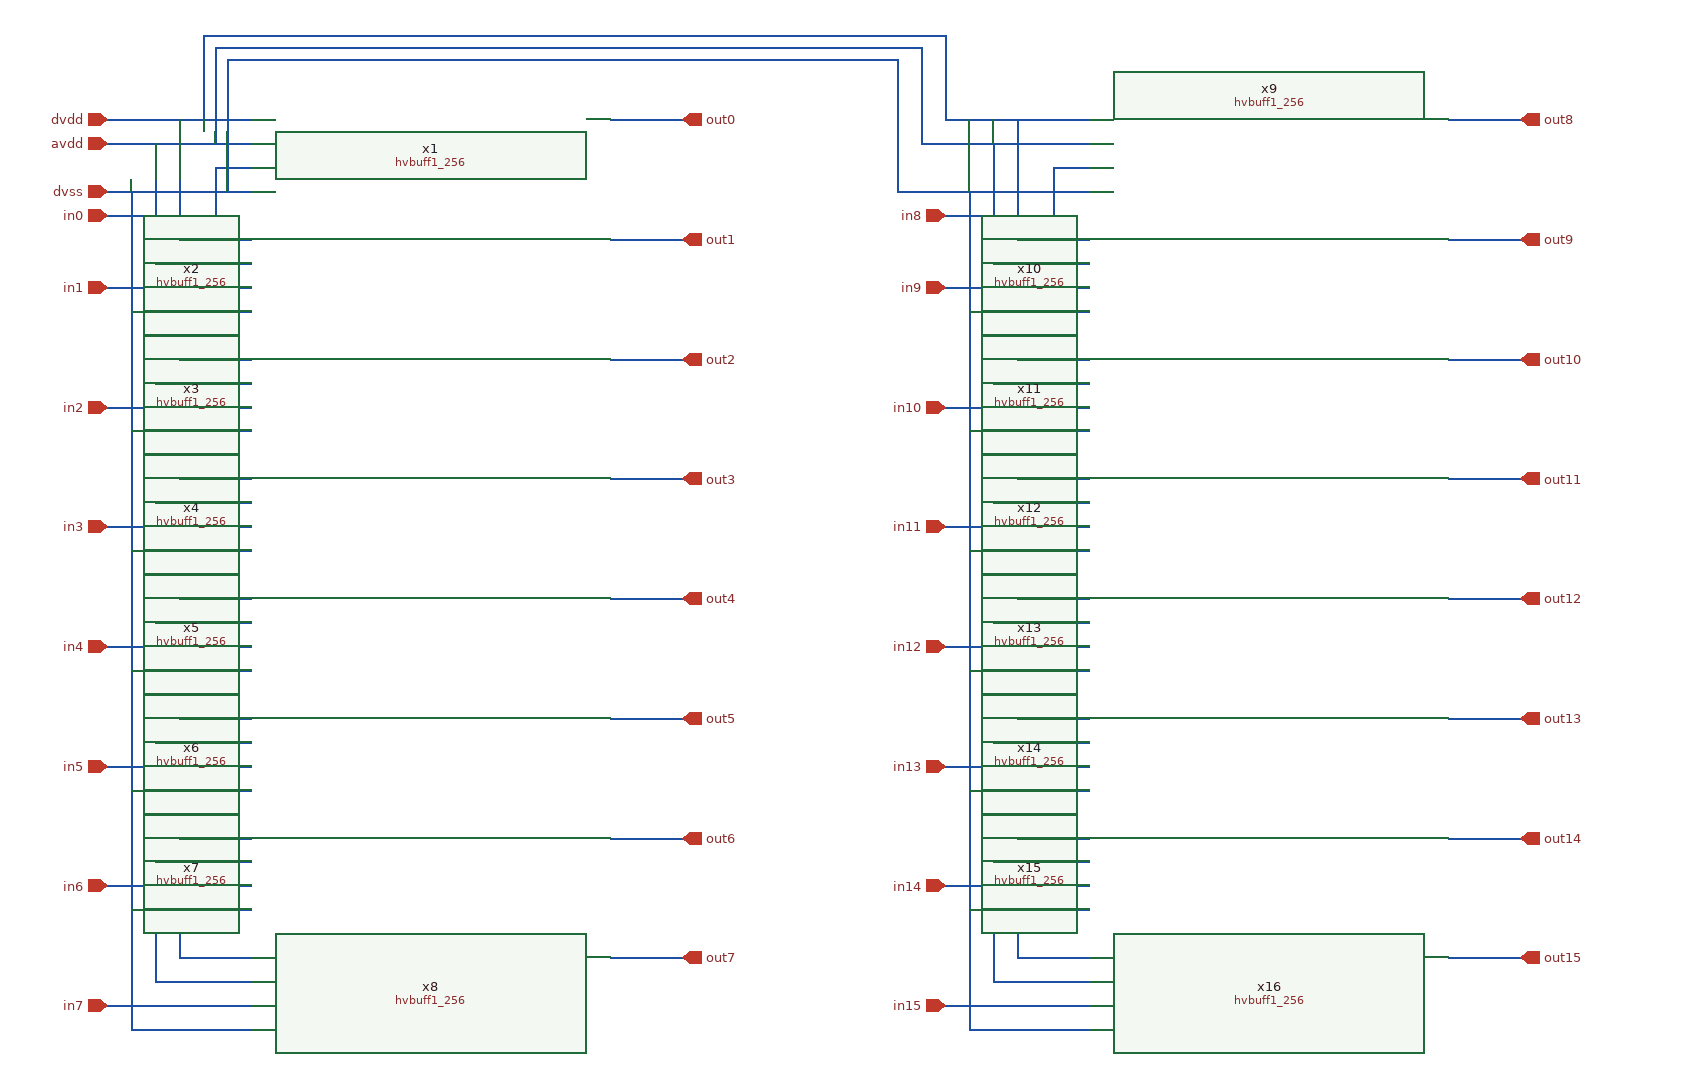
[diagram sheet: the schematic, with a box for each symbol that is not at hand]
v {xschem version=3.4.5 file_version=1.2
}
G {}
K {}
V {}
S {}
E {}
N -250 -70 -130 -70 {
lab=dvdd}
N -190 -70 -190 630 {
lab=dvdd}
N -190 630 -130 630 {
lab=dvdd}
N -190 530 -130 530 {
lab=dvdd}
N -190 430 -130 430 {
lab=dvdd}
N -190 330 -130 330 {
lab=dvdd}
N -190 230 -130 230 {
lab=dvdd}
N -190 130 -130 130 {
lab=dvdd}
N -190 30 -130 30 {
lab=dvdd}
N -250 -50 -130 -50 {
lab=avdd}
N -210 -50 -210 650 {
lab=avdd}
N -210 650 -130 650 {
lab=avdd}
N -210 550 -130 550 {
lab=avdd}
N -210 450 -130 450 {
lab=avdd}
N -210 350 -130 350 {
lab=avdd}
N -210 250 -130 250 {
lab=avdd}
N -210 150 -130 150 {
lab=avdd}
N -210 50 -130 50 {
lab=avdd}
N -250 -10 -130 -10 {
lab=dvss}
N -230 -10 -230 690 {
lab=dvss}
N -230 690 -130 690 {
lab=dvss}
N -230 590 -130 590 {
lab=dvss}
N -230 490 -130 490 {
lab=dvss}
N -230 390 -130 390 {
lab=dvss}
N -230 290 -130 290 {
lab=dvss}
N -230 190 -130 190 {
lab=dvss}
N -230 90 -130 90 {
lab=dvss}
N -160 -30 -130 -30 {
lab=in0}
N -160 -30 -160 10 {
lab=in0}
N -250 10 -160 10 {
lab=in0}
N -250 70 -130 70 {
lab=in1}
N -250 170 -130 170 {
lab=in2}
N -250 270 -130 270 {
lab=in3}
N -250 370 -130 370 {
lab=in4}
N -250 470 -130 470 {
lab=in5}
N -250 570 -130 570 {
lab=in6}
N -250 670 -130 670 {
lab=in7}
N 170 -70 230 -70 {
lab=out0}
N 170 30 230 30 {
lab=out1}
N 170 130 230 130 {
lab=out2}
N 170 230 230 230 {
lab=out3}
N 170 330 230 330 {
lab=out4}
N 170 430 230 430 {
lab=out5}
N 170 530 230 530 {
lab=out6}
N 170 630 230 630 {
lab=out7}
N 450 -70 570 -70 {
lab=dvdd}
N 510 -70 510 630 {
lab=dvdd}
N 510 630 570 630 {
lab=dvdd}
N 510 530 570 530 {
lab=dvdd}
N 510 430 570 430 {
lab=dvdd}
N 510 330 570 330 {
lab=dvdd}
N 510 230 570 230 {
lab=dvdd}
N 510 130 570 130 {
lab=dvdd}
N 510 30 570 30 {
lab=dvdd}
N 450 -50 570 -50 {
lab=avdd}
N 490 -50 490 650 {
lab=avdd}
N 490 650 570 650 {
lab=avdd}
N 490 550 570 550 {
lab=avdd}
N 490 450 570 450 {
lab=avdd}
N 490 350 570 350 {
lab=avdd}
N 490 250 570 250 {
lab=avdd}
N 490 150 570 150 {
lab=avdd}
N 490 50 570 50 {
lab=avdd}
N 450 -10 570 -10 {
lab=dvss}
N 470 -10 470 690 {
lab=dvss}
N 470 690 570 690 {
lab=dvss}
N 470 590 570 590 {
lab=dvss}
N 470 490 570 490 {
lab=dvss}
N 470 390 570 390 {
lab=dvss}
N 470 290 570 290 {
lab=dvss}
N 470 190 570 190 {
lab=dvss}
N 470 90 570 90 {
lab=dvss}
N 540 -30 570 -30 {
lab=in8}
N 540 -30 540 10 {
lab=in8}
N 450 10 540 10 {
lab=in8}
N 450 70 570 70 {
lab=in9}
N 450 170 570 170 {
lab=in10}
N 450 270 570 270 {
lab=in11}
N 450 370 570 370 {
lab=in12}
N 450 470 570 470 {
lab=in13}
N 450 570 570 570 {
lab=in14}
N 450 670 570 670 {
lab=in15}
N 870 -70 930 -70 {
lab=out0}
N 870 30 930 30 {
lab=out9}
N 870 130 930 130 {
lab=out10}
N 870 230 930 230 {
lab=out11}
N 870 330 930 330 {
lab=out12}
N 870 430 930 430 {
lab=out13}
N 870 530 930 530 {
lab=out14}
N 870 630 930 630 {
lab=out15}
N -170 -140 -170 -70 {
lab=dvdd}
N -170 -140 450 -140 {
lab=dvdd}
N 450 -140 450 -70 {
lab=dvdd}
N 430 -50 450 -50 {
lab=avdd}
N -160 -130 -160 -50 {
lab=avdd}
N -160 -130 430 -130 {
lab=avdd}
N 430 -130 430 -50 {
lab=avdd}
N -150 -120 -150 -10 {
lab=dvss}
N -150 -120 410 -120 {
lab=dvss}
N 410 -120 410 -10 {
lab=dvss}
N 410 -10 450 -10 {
lab=dvss}
C {hvbuff1_256.sym} 20 -40 0 0 {name=x1}
C {hvbuff1_256.sym} 20 60 0 0 {name=x2}
C {hvbuff1_256.sym} 20 160 0 0 {name=x3}
C {hvbuff1_256.sym} 20 260 0 0 {name=x4}
C {hvbuff1_256.sym} 20 360 0 0 {name=x5}
C {hvbuff1_256.sym} 20 460 0 0 {name=x6}
C {hvbuff1_256.sym} 20 560 0 0 {name=x7}
C {hvbuff1_256.sym} 20 660 0 0 {name=x8}
C {devices/opin.sym} 230 -70 0 0 {name=p1 lab=out0}
C {devices/opin.sym} 230 30 0 0 {name=p2 lab=out1}
C {devices/opin.sym} 230 130 0 0 {name=p3 lab=out2}
C {devices/opin.sym} 230 230 0 0 {name=p4 lab=out3}
C {devices/opin.sym} 230 330 0 0 {name=p5 lab=out4}
C {devices/opin.sym} 230 430 0 0 {name=p6 lab=out5}
C {devices/opin.sym} 230 530 0 0 {name=p7 lab=out6}
C {devices/opin.sym} 230 630 0 0 {name=p8 lab=out7}
C {devices/ipin.sym} -250 10 0 0 {name=p9 lab=in0}
C {devices/ipin.sym} -250 70 0 0 {name=p10 lab=in1}
C {devices/ipin.sym} -250 170 0 0 {name=p11 lab=in2}
C {devices/ipin.sym} -250 270 0 0 {name=p12 lab=in3}
C {devices/ipin.sym} -250 370 0 0 {name=p13 lab=in4}
C {devices/ipin.sym} -250 470 0 0 {name=p14 lab=in5}
C {devices/ipin.sym} -250 570 0 0 {name=p15 lab=in6}
C {devices/ipin.sym} -250 670 0 0 {name=p16 lab=in7}
C {hvbuff1_256.sym} 720 -40 0 0 {name=x9}
C {hvbuff1_256.sym} 720 60 0 0 {name=x10}
C {hvbuff1_256.sym} 720 160 0 0 {name=x11}
C {hvbuff1_256.sym} 720 260 0 0 {name=x12}
C {hvbuff1_256.sym} 720 360 0 0 {name=x13}
C {hvbuff1_256.sym} 720 460 0 0 {name=x14}
C {hvbuff1_256.sym} 720 560 0 0 {name=x15}
C {hvbuff1_256.sym} 720 660 0 0 {name=x16}
C {devices/opin.sym} 930 -70 0 0 {name=p17 lab=out8}
C {devices/opin.sym} 930 30 0 0 {name=p18 lab=out9}
C {devices/opin.sym} 930 130 0 0 {name=p19 lab=out10}
C {devices/opin.sym} 930 230 0 0 {name=p20 lab=out11}
C {devices/opin.sym} 930 330 0 0 {name=p21 lab=out12}
C {devices/opin.sym} 930 430 0 0 {name=p22 lab=out13}
C {devices/opin.sym} 930 530 0 0 {name=p23 lab=out14}
C {devices/opin.sym} 930 630 0 0 {name=p24 lab=out15}
C {devices/ipin.sym} 450 10 0 0 {name=p25 lab=in8}
C {devices/ipin.sym} 450 70 0 0 {name=p26 lab=in9}
C {devices/ipin.sym} 450 170 0 0 {name=p27 lab=in10}
C {devices/ipin.sym} 450 270 0 0 {name=p28 lab=in11}
C {devices/ipin.sym} 450 370 0 0 {name=p29 lab=in12}
C {devices/ipin.sym} 450 470 0 0 {name=p30 lab=in13}
C {devices/ipin.sym} 450 570 0 0 {name=p31 lab=in14}
C {devices/ipin.sym} 450 670 0 0 {name=p32 lab=in15}
C {devices/ipin.sym} -250 -70 0 0 {name=p33 lab=dvdd}
C {devices/ipin.sym} -250 -50 0 0 {name=p34 lab=avdd}
C {devices/ipin.sym} -250 -10 0 0 {name=p35 lab=dvss}
